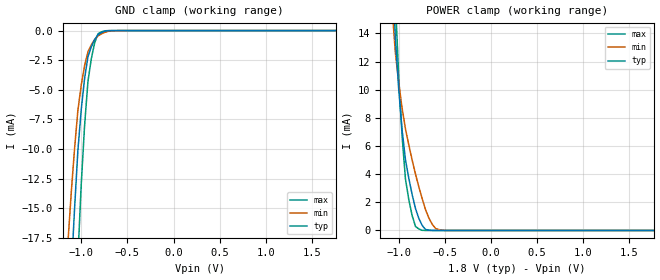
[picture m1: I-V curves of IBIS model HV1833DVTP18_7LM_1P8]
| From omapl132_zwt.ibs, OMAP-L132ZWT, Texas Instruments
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|NOSR0_NOTERM_0.1_1P8
|BUFFER OPERATING AT FAST MODE WITH 1.8V SUPPLY WITH +/-0.1V VARIATION
|   Model Cell HV1833DVTP18_7LM_1P8
|IHHV1833DVTP18_1P8
[Model]   HV1833DVTP18_7LM_1P8
Model_type   Input
Polarity   Non-Inverting
Vinl =  0.63V   | Input logic Low DC Voltage
Vinh =  1.17V   | Input logic High DC Voltage
C_comp   0.7294814p   0.6184726p   0.8493104p
[Model Spec]
Vinl   0.63V   0.567V   0.693V
Vinh   1.17V   1.053V   1.287V
| variable   typ (C)   max (C)   min (C)
[Temperature Range]   25   125   -40
| variable   typ   min   max
[Voltage Range]   1.8   1.62   1.98
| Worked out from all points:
|   GND clamp passes 1 mA (typ) near -0.87 V on its own axis
|   POWER clamp passes 1 mA (typ) near -0.79 V on its own axis
[POWER_clamp]
|   voltage   I(typ)   I(min)   I(max)
-1.8V     187.7mA    158.1mA    215.5mA
-1.073V   18.99mA    15.82mA    23.57mA
-1.036V   13.65mA    12.62mA    16.33mA
-1V       10.01mA    10.49mA    10.92mA
-963.6mV  7.141mA    8.694mA    6.699mA
-927.3mV  5.03mA     7.227mA    3.67mA
-854.5mV  2.547mA    5mA        1.054mA
-781.8mV  850.9uA    3.095mA    106.6uA
-709.1mV  68.54uA    1.464mA    1.258uA
-636.4mV  4.105uA    432.7uA    198.1nA
-527.3mV  67.96nA    16.14uA    110.9nA
1.764V    -2.173pA   -498.8pA   -4.977pA
[GND_clamp]
|   voltage   I(typ)   I(min)   I(max)
-1.8V     -165.1mA   -131.7mA   -236.3mA
-1.145V   -26.58mA   -18.01mA   -45.04mA
-1.109V   -20.58mA   -13.76mA   -35.89mA
-1.073V   -15.09mA   -10.01mA   -27.27mA
-1.036V   -10.13mA   -6.739mA   -19.19mA
-1V       -6.678mA   -4.606mA   -12.98mA
-963.6mV  -4.038mA   -2.956mA   -8.012mA
-927.3mV  -2.206mA   -1.79mA    -4.293mA
-854.5mV  -757uA     -757.6uA   -1.04mA
-818.2mV  -351.4uA   -449.1uA   -270.3uA
-600mV    -377.8nA   -4.974uA   -26.71nA
1.764V    22.6nA     12.56nA    79.89nA
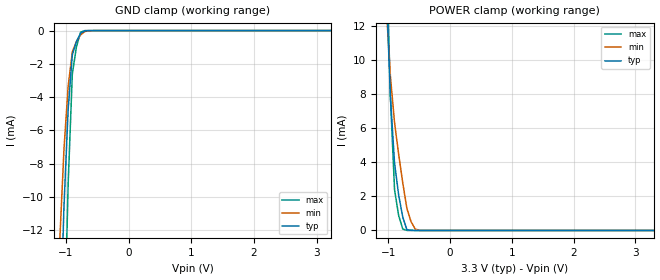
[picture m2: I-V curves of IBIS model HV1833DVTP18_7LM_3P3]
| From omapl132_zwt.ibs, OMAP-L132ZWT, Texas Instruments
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|   Model Cell HV1833DVTP18_7LM_3P3
|IHHV1833DVTP18_3P3
[Model]   HV1833DVTP18_7LM_3P3
Model_type   Input
Polarity   Non-Inverting
Vinl =  0.8V
Vinh =  2V
C_comp   0.6935759p   0.5873084p   0.8051541p
[Model Spec]
Vinl   0.8V   0.8V   0.8V
Vinh   2V   2V   2V
[Temperature Range]   25   125   -40
[Voltage Range]   3.3   2.97   3.63
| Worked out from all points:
|   GND clamp passes 1 mA (typ) near -0.86 V on its own axis
|   POWER clamp passes 1 mA (typ) near -0.78 V on its own axis
[POWER_clamp]
|   voltage   I(typ)   I(min)   I(max)
-3.3V     577mA      699.3mA    642.1mA
-1.033V   14.21mA    13.03mA    16.74mA
-966.7mV  7.793mA    9.007mA    7.813mA
-900mV    3.948mA    6.325mA    2.381mA
-833.3mV  2.08mA     4.462mA    876uA
-766.7mV  779.2uA    2.784mA    82.54uA
-700mV    46.09uA    1.291mA    978.9nA
-633.3mV  15.73uA    522.4uA    478.6nA
-566.7mV  388.5nA    93.56uA    220.2nA
-500mV    49.53nA    4.585uA    203.5nA
3.3V      -3.663pA   -14.5nA    -1.514pA
[GND_clamp]
|   voltage   I(typ)   I(min)   I(max)
-3.3V     -508.9mA   -631.8mA   -692.1mA
-1.1V     -18.99mA   -12.61mA   -33.52mA
-1.033V   -10.59mA   -7.151mA   -19.56mA
-966.7mV  -4.748mA   -3.373mA   -9.253mA
-900mV    -1.465mA   -1.277mA   -2.61mA
-833.3mV  -642.1uA   -655.9uA   -961.1uA
-766.7mV  -157.4uA   -248uA     -91.61uA
-700mV    -10.5uA    -52.92uA   -1.769uA
-566.7mV  -258nA     -3.484uA   -18.04nA
3.233V    32.19nA    19.88nA    142.8nA
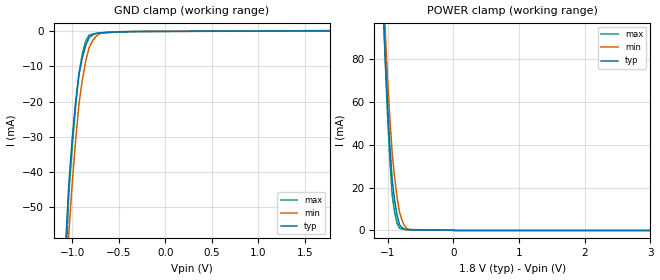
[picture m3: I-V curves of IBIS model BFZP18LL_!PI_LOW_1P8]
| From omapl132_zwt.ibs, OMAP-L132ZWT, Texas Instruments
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|   Model Cell BFZP18LL_!PI_LOW_1P8
|IC1833DVTPBFZP18LL_!PI_LOW_1P8
[Model]   BFZP18LL_!PI_LOW_1P8
Model_type   Input
Polarity   Non-Inverting
Vinl =  0.63
Vinh =  1.17
C_comp   1.254226p   1.200533p   1.264851p
[Model Spec]
Vinl   0.63   0.567   0.693
Vinh   1.17   1.053   1.287
[Temperature Range]   25   125   -40
[Voltage Range]   1.8   1.62   1.98
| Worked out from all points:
|   GND clamp passes 1 mA (typ) near -0.78 V on its own axis
|   POWER clamp passes 1 mA (typ) near -0.76 V on its own axis
[POWER_clamp]
|   voltage   I(typ)   I(min)   I(max)
-1.8V     812.6mA    848.7mA    874.9mA
-1.073V   110.1mA    121.8mA    111.5mA
-1.036V   82.05mA    94.39mA    79.98mA
-1V       58.78mA    71.71mA    53.95mA
-963.6mV  39.1mA     52.05mA    32.63mA
-927.3mV  23.01mA    35.4mA     16.03mA
-890.9mV  13.9mA     24.43mA    8.35mA
-854.5mV  7.152mA    15.52mA    3.351mA
-818.2mV  2.762mA    8.67mA     1.037mA
-709.1mV  356.9uA    948.4uA    479.4uA
-600mV    244.4uA    168.4uA    396.4uA
3.6V      0A         0A         0A
[GND_clamp]
|   voltage   I(typ)   I(min)   I(max)
-1.8V     -593.4mA   -494.6mA   -853.3mA
-1.073V   -62.14mA   -74.14mA   -68.27mA
-1.036V   -43.78mA   -57.66mA   -46.67mA
-1V       -30.76mA   -43.65mA   -33.12mA
-963.6mV  -20.29mA   -31.35mA   -21.59mA
-927.3mV  -12.34mA   -20.77mA   -12.06mA
-890.9mV  -7.584mA   -13.9mA    -6.435mA
-854.5mV  -4.05mA    -8.522mA   -2.773mA
-818.2mV  -1.744mA   -4.623mA   -1.075mA
-745.5mV  -590uA     -1.44mA    -606.5uA
-600mV    -239.8uA   -203.1uA   -329.9uA
1.764V    148.6uA    81.33uA    236.4uA
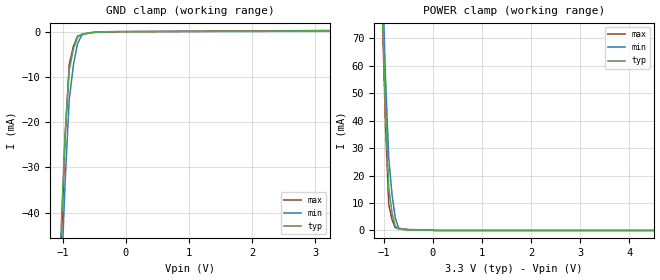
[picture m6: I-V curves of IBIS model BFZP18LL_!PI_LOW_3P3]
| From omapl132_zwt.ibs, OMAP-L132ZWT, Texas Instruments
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|   Model Cell BFZP18LL_!PI_LOW_3P3
|IC1833DVTPBFZP18LL_!PI_LOW_3P3
[Model]   BFZP18LL_!PI_LOW_3P3
Model_type   Input
Polarity   Non-Inverting
Vinl =  0.8V
Vinh =  2V
C_comp   1.012258p   0.8890016p   1.091755p
[Model Spec]
Vinl   0.8V   0.8V   0.8V
Vinh   2V   2V   2V
[Temperature Range]   25   125   -40
[Voltage Range]   3.3   2.97   3.63
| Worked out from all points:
|   GND clamp passes 1 mA (typ) near -0.75 V on its own axis
|   POWER clamp passes 1 mA (typ) near -0.73 V on its own axis
[POWER_clamp]
|   voltage   I(typ)   I(min)   I(max)
-3.3V     2.37A      2.826A     2.542A
-1.033V   82.55mA    94.89mA    80.63mA
-966.7mV  43.74mA    56mA       38.48mA
-900mV    15.37mA    26.34mA    9.446mA
-833.3mV  6.478mA    13.09mA    3.923mA
-766.7mV  1.541mA    4.609mA    1.023mA
-700mV    561.3uA    908.1uA    746uA
-500mV    250.8uA    144uA      374.7uA
-33.33mV  156.6uA    79.82uA    267.8uA
33.33mV   0A         0A         0A
6.6V      0A         0A         0A
[GND_clamp]
|   voltage   I(typ)   I(min)   I(max)
-3.3V     -1.792A    -1.668A    -2.631A
-1.033V   -45.54mA   -57.75mA   -50.28mA
-966.7mV  -22.83mA   -33.83mA   -24.05mA
-900mV    -8.523mA   -15.06mA   -7.278mA
-833.3mV  -3.829mA   -7.372mA   -3.202mA
-766.7mV  -1.175mA   -2.601mA   -991.4uA
-700mV    -560.3uA   -746.6uA   -646.9uA
-566.7mV  -249.1uA   -234.1uA   -286.4uA
-300mV    -29.03uA   -23.37uA   -39.39uA
3.233V    153.5uA    84.96uA    245.7uA
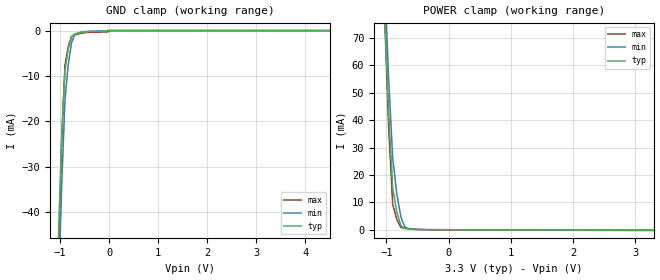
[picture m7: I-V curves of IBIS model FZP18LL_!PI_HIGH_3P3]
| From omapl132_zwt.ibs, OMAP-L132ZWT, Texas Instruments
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|   Model Cell FZP18LL_!PI_HIGH_3P3
|IC1833DVTPBFZP18LL_!PI_HIGH_3P3
[Model]   FZP18LL_!PI_HIGH_3P3
Model_type   Input
Polarity   Non-Inverting
Vinl =  0.8V
Vinh =  2V
C_comp   1.012258p   0.8890016p   1.091755p
[Model Spec]
Vinl   0.8V   0.8V   0.8V
Vinh   2V   2V   2V
[Temperature Range]   25   125   -40
[Voltage Range]   3.3   2.97   3.63
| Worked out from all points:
|   GND clamp passes 1 mA (typ) near -0.73 V on its own axis
|   POWER clamp passes 1 mA (typ) near -0.74 V on its own axis
[POWER_clamp]
|   voltage   I(typ)   I(min)   I(max)
-3.3V     2.37A      2.826A     2.542A
-1.033V   82.45mA    94.83mA    80.46mA
-966.7mV  43.63mA    55.94mA    38.29mA
-900mV    15.26mA    26.28mA    9.25mA
-833.3mV  6.36mA     13.02mA    3.719mA
-766.7mV  1.419mA    4.545mA    812.7uA
-700mV    434.9uA    841.8uA    529.8uA
-500mV    114.3uA    72.51uA    142.6uA
3.3V      -177.5uA   -119.9uA   -277.3uA
[GND_clamp]
|   voltage   I(typ)   I(min)   I(max)
-3.3V     -1.792A    -1.668A    -2.631A
-1.033V   -45.64mA   -57.8mA    -50.41mA
-966.7mV  -22.95mA   -33.88mA   -24.23mA
-900mV    -8.666mA   -15.12mA   -7.531mA
-833.3mV  -3.992mA   -7.446mA   -3.487mA
-766.7mV  -1.349mA   -2.684mA   -1.294mA
-700mV    -737.3uA   -833.8uA   -950.7uA
-500mV    -322.4uA   -220.3uA   -476.2uA
-100mV    -182.9uA   -91.68uA   -313.4uA
-33.33mV  0A         0A         -307.8uA
33.33mV   0A         0A         0A
6.6V      0A         0A         0A
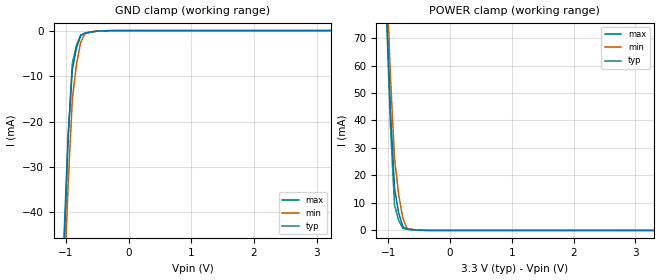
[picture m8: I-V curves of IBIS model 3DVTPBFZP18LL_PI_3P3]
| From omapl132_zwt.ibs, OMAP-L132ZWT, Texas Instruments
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|   Model Cell 3DVTPBFZP18LL_PI_3P3
|IC1833DVTPBFZP18LL_PI_3P3
[Model]   3DVTPBFZP18LL_PI_3P3
Model_type   Input
Polarity   Non-Inverting
Vinl =  0.8V
Vinh =  2V
C_comp   1.012258p   0.8890016p   1.091755p
[Model Spec]
Vinl   0.8V   0.8V   0.8V
Vinh   2V   2V   2V
[Temperature Range]   25   125   -40
[Voltage Range]   3.3   2.97   3.63
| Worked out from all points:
|   GND clamp passes 1 mA (typ) near -0.75 V on its own axis
|   POWER clamp passes 1 mA (typ) near -0.74 V on its own axis
[POWER_clamp]
|   voltage   I(typ)   I(min)   I(max)
-3.3V     2.37A      2.826A     2.542A
-1.033V   82.43mA    94.82mA    80.43mA
-966.7mV  43.62mA    55.93mA    38.27mA
-900mV    15.24mA    26.27mA    9.222mA
-833.3mV  6.342mA    13.01mA    3.689mA
-766.7mV  1.399mA    4.534mA    780.9uA
-700mV    414.7uA    830.8uA    496.6uA
-500mV    93.22uA    61.22uA    108uA
3.3V      -347.5pA   -21.71uA   -26.25pA
[GND_clamp]
|   voltage   I(typ)   I(min)   I(max)
-3.3V     -1.792A    -1.668A    -2.631A
-1.033V   -45.54mA   -57.75mA   -50.28mA
-966.7mV  -22.82mA   -33.83mA   -24.04mA
-900mV    -8.515mA   -15.06mA   -7.265mA
-833.3mV  -3.815mA   -7.367mA   -3.174mA
-766.7mV  -1.156mA   -2.594mA   -954.7uA
-700mV    -537uA     -736.9uA   -606.1uA
-566.7mV  -224.7uA   -222.5uA   -244.9uA
-433.3mV  -72.81uA   -71.22uA   -81.46uA
3.233V    1.162uA    1.668uA    3.191uA
